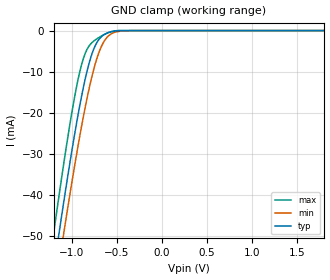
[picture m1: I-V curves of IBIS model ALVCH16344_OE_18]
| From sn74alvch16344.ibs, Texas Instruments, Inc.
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[Model]   ALVCH16344_OE_18
Model_type  Input
Vinl = 0.5775
Vinh = 1.2675
| variable   typ   min   max
C_comp   1.70pF   1.60pF   1.82pF
[Temperature Range]   40   100   -40
| Ambient temperature   25   85   -40
[Voltage range]   1.8   1.65   1.95
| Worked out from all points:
|   GND clamp passes 1 mA (typ) near -0.64 V on its own axis
[GND Clamp]
| ALVCH16344_OE_18
|   Voltage   I(typ)   I(min)   I(max)
-1.8V     -154.1mA   -159mA     -149mA
-1.2V     -58.39mA   -65.68mA   -49.51mA
-1.14V    -49.45mA   -56.93mA   -40.29mA
-1.09V    -42.19mA   -49.79mA   -32.85mA
-1.075V   -40.05mA   -47.68mA   -30.68mA
-970mV    -25.77mA   -33.43mA   -16.64mA
-885mV    -15.57mA   -22.84mA   -7.999mA
-785mV    -6.445mA   -12.18mA   -3.188mA
-695mV    -2.131mA   -5.276mA   -1.676mA
-590mV    -475.3uA   -1.289mA   -495.7uA
-450mV    -11.4uA    -130.5uA   -721.9nA
1.8V      1.117nA    59.63nA    5.149pA
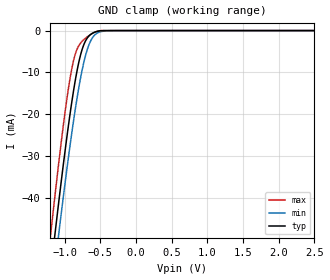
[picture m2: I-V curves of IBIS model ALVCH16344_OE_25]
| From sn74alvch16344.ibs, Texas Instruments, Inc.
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[Model]   ALVCH16344_OE_25
Model_type  Input
Vinl = 0.7
Vinh = 1.7
| variable   typ   min   max
C_comp   1.72pF   1.53pF   1.91pF
[Temperature Range]   40   100   -40
| Ambient temperature   25   85   -40
[Voltage range]   2.5   2.3   2.7
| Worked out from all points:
|   GND clamp passes 1 mA (typ) near -0.64 V on its own axis
[GND Clamp]
| ALVCH16344_OE_25
|   Voltage   I(typ)   I(min)   I(max)
-2.5V     -271.2mA   -273.1mA   -270.4mA
-1.2V     -58.39mA   -65.68mA   -49.51mA
-1.18V    -55.38mA   -62.74mA   -46.4mA
-1.13V    -47.98mA   -55.49mA   -38.78mA
-1.08V    -40.76mA   -48.38mA   -31.4mA
-960mV    -24.49mA   -32.13mA   -15.45mA
-865mV    -13.44mA   -20.52mA   -6.558mA
-740mV    -3.816mA   -8.342mA   -2.321mA
-675mV    -1.628mA   -4.185mA   -1.414mA
-605mV    -602.9uA   -1.621mA   -627.2uA
-365mV    -1.926uA   -30.65uA   -28.14nA
2.5V      1.121nA    59.64nA    7.252pA
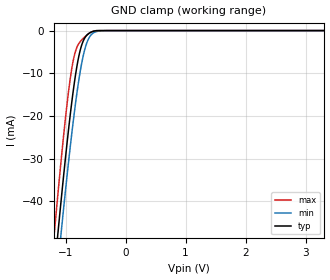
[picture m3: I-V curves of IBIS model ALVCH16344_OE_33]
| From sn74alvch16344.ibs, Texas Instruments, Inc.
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[Model]   ALVCH16344_OE_33
Model_type  Input
Vinl = 0.8
Vinh = 2.0
| variable   typ   min   max
C_comp   1.71pF   1.47pF   2.00pF
[Temperature Range]   40   100   -40
| Ambient temperature   25   85   -40
[Voltage range]   3.3   3   3.6
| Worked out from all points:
|   GND clamp passes 1 mA (typ) near -0.64 V on its own axis
[GND Clamp]
| ALVCH16344_OE_33
|   Voltage   I(typ)   I(min)   I(max)
-3.3V     -407.3mA   -405.9mA   -411.3mA
-1.19V    -56.88mA   -64.21mA   -47.95mA
-1.125V   -47.25mA   -54.77mA   -38.03mA
-1.085V   -41.47mA   -49.08mA   -32.13mA
-1.065V   -38.63mA   -46.28mA   -29.25mA
-960mV    -24.49mA   -32.13mA   -15.45mA
-860mV    -12.93mA   -19.95mA   -6.239mA
-740mV    -3.816mA   -8.342mA   -2.321mA
-665mV    -1.42mA    -3.702mA   -1.288mA
-585mV    -437.3uA   -1.192mA   -455.1uA
-350mV    -1.412uA   -23.67uA   -16.13nA
3.3V      1.125nA    59.65nA    9.668pA
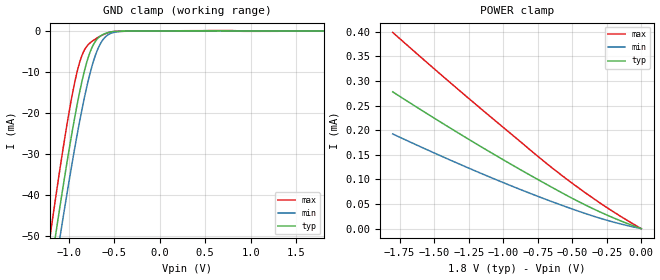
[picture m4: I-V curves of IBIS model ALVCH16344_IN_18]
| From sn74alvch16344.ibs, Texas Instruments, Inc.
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[Model]   ALVCH16344_IN_18
Model_type  Input
Vinl = 0.5775
Vinh = 1.2675
| variable   typ   min   max
C_comp   2.46pF   2.18pF   2.79pF
[Temperature Range]   40   100   -40
| Ambient temperature   25   85   -40
[Voltage range]   1.8   1.65   1.95
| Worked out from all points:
|   GND clamp passes 1 mA (typ) near -0.63 V on its own axis
[GND Clamp]
| ALVCH16344_IN_18
|   Voltage   I(typ)   I(min)   I(max)
-1.8V     -154.5mA   -159.2mA   -149.5mA
-1.205V   -59.36mA   -66.56mA   -50.62mA
-1.185V   -56.34mA   -63.61mA   -47.5mA
-1.145V   -50.39mA   -57.78mA   -41.35mA
-1.09V    -42.38mA   -49.91mA   -33.15mA
-970mV    -25.94mA   -33.53mA   -16.89mA
-885mV    -15.72mA   -22.93mA   -8.227mA
-785mV    -6.577mA   -12.27mA   -3.385mA
-695mV    -2.245mA   -5.349mA   -1.845mA
-605mV    -699.2uA   -1.682mA   -770uA
-465mV    -85uA      -212uA     -105.7uA
1.8V      1.12nA     9.574uA    -22.72uA
[POWER Clamp]
| ALVCH16344_IN_18
|   Voltage   I(typ)   I(min)   I(max)
-1.8V     278uA      192.5uA    398.9uA
-1.2V     173.2uA    117.1uA    252.9uA
-645mV    83.65uA    54.66uA    123.4uA
-480mV    58.73uA    37.93uA    88.08uA
-315mV    36.04uA    22.58uA    55.28uA
-155mV    16.49uA    9.93uA     25.95uA
-16.28fV  1.12nA     59.64nA    8.716pA
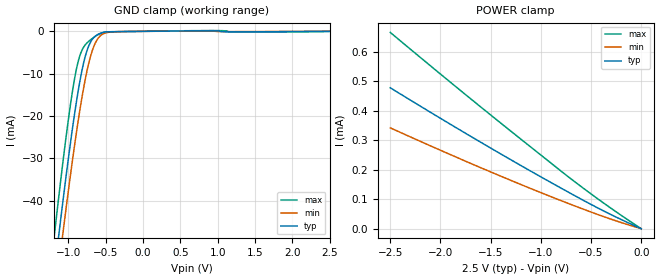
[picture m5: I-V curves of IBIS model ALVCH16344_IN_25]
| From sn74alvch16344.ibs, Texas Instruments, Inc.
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[Model]   ALVCH16344_IN_25
Model_type  Input
Vinl = 0.7
Vinh = 1.7
| variable   typ   min   max
C_comp   2.54pF   2.03pF   2.93pF
[Temperature Range]   40   100   -40
| Ambient temperature   25   85   -40
[Voltage range]   2.5   2.3   2.7
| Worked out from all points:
|   GND clamp passes 1 mA (typ) near -0.63 V on its own axis
[GND Clamp]
| ALVCH16344_IN_25
|   Voltage   I(typ)   I(min)   I(max)
-2.5V     -271.7mA   -273.5mA   -271.2mA
-1.195V   -57.91mA   -65.13mA   -49.13mA
-1.16V    -52.67mA   -60mA      -43.71mA
-1.125V   -47.5mA    -54.94mA   -38.4mA
-1.075V   -40.29mA   -47.84mA   -31.04mA
-960mV    -24.7mA    -32.27mA   -15.77mA
-865mV    -13.63mA   -20.65mA   -6.836mA
-745mV    -4.221mA   -8.841mA   -2.636mA
-670mV    -1.665mA   -4.035mA   -1.559mA
-600mV    -685.2uA   -1.589mA   -766.6uA
-305mV    -60.79uA   -50.66uA   -89.26uA
2.5V      1.125nA    20.81uA    -42.68uA
[POWER Clamp]
| ALVCH16344_IN_25
|   Voltage   I(typ)   I(min)   I(max)
-2.5V     477.5uA    341.7uA    665.3uA
-1.6V     293.2uA    206.8uA    412.9uA
-775mV    133uA      91.91uA    188.8uA
-380mV    61.1uA     41.52uA    88.18uA
-31.15fV  1.125nA    59.64nA    12.15pA
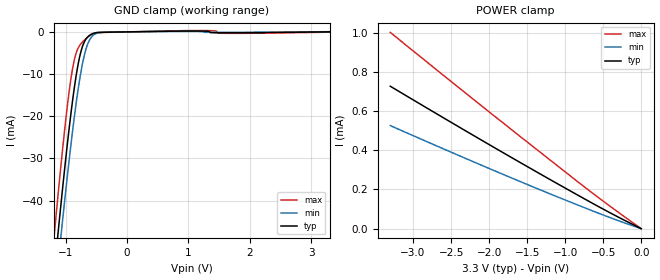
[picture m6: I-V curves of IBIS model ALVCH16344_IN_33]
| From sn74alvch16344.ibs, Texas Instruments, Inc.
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[Model]   ALVCH16344_IN_33
Model_type  Input
Vinl = 0.8
Vinh = 2.0
| variable   typ   min   max
C_comp   2.58pF   1.96pF   3.05pF
[Temperature Range]   40   100   -40
| Ambient temperature   25   85   -40
[Voltage range]   3.3   3   3.6
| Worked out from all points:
|   GND clamp passes 1 mA (typ) near -0.63 V on its own axis
[GND Clamp]
| ALVCH16344_IN_33
|   Voltage   I(typ)   I(min)   I(max)
-3.3V     -408.2mA   -406.6mA   -412.6mA
-1.185V   -56.46mA   -63.7mA    -47.64mA
-1.12V    -46.83mA   -54.26mA   -37.72mA
-1.08V    -41.05mA   -48.58mA   -31.82mA
-1.065V   -38.92mA   -46.47mA   -29.67mA
-950mV    -23.49mA   -31.02mA   -14.67mA
-860mV    -13.16mA   -20.11mA   -6.569mA
-730mV    -3.559mA   -7.722mA   -2.445mA
-655mV    -1.41mA    -3.379mA   -1.412mA
-580mV    -552.6uA   -1.206mA   -633.9uA
-270mV    -67.94uA   -51.6uA    -98.78uA
3.3V      1.131nA    40.72uA    -79.23uA
[POWER Clamp]
| ALVCH16344_IN_33
|   Voltage   I(typ)   I(min)   I(max)
-3.3V     726.6uA    525.8uA    1.001mA
-1.955V   418.9uA    299.7uA    582uA
-845mV    173.4uA    122.2uA    242.6uA
-430mV    85.18uA    59.42uA    120.2uA
-48.03fV  1.131nA    59.65nA    16.28pA
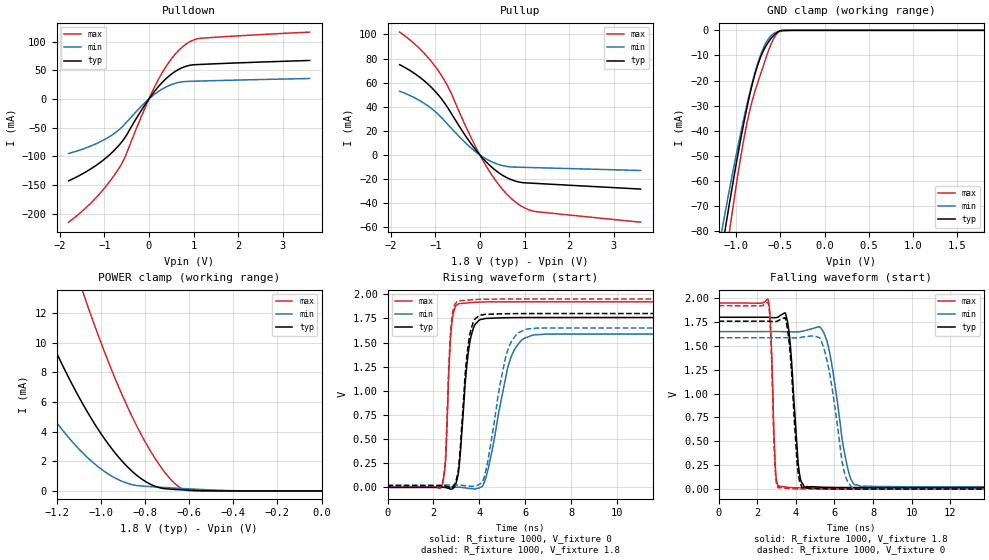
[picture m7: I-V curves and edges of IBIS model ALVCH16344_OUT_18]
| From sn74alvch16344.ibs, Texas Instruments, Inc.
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[Model]   ALVCH16344_OUT_18
Model_type  3-state
Enable   Active-Low
Vref =   0
Rref =   1000
Cref =   30p
Vmeas =   0.9
| variable   typ   min   max
C_comp   4.31pF   3.88pF   4.55pF
| C_pullup   5.53pF   4.17pF   6.17pF
| C_pulldown   8.54pF   4.73pF   11.91pF
| C_tri-state   4.31pF   3.88pF   4.55pF
[Temperature Range]   40   100   -40
| Ambient temperature   25   85   -40
[Voltage range]   1.8   1.65   1.95
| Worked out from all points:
|   slope of the pulldown table from 0 to 0.27 V, typ, clamps not added: 10.2 ohm
|   slope of the pullup table from 0 to 0.27 V, typ, clamps not added: 26.4 ohm
|   GND clamp passes 1 mA (typ) near -0.54 V on its own axis
|   POWER clamp passes 1 mA (typ) near -0.83 V on its own axis
|   rising waveform, R_fixture 1000, V_fixture 0: 20-80 % time 355ps typ, 776ps min, 195ps max; typ from 0 V to 1.76 V
|   falling waveform, R_fixture 1000, V_fixture 1.8: 20-80 % time 344ps typ, 701ps min, 181ps max; typ from 1.8 V to 0.016 V
|   rising waveform, R_fixture 1000, V_fixture 1.8: 20-80 % time 339ps typ, 702ps min, 189ps max; typ from 0.016 V to 1.8 V
|   falling waveform, R_fixture 1000, V_fixture 0: 20-80 % time 329ps typ, 676ps min, 176ps max; typ from 1.76 V to 0 V
[GND Clamp]
| ALVCH16344_OUT_18
|   Voltage   I(typ)   I(min)   I(max)
-1.8V     -239.8mA   -213.3mA   -281.9mA
-1.165V   -87.9mA    -80.05mA   -102.5mA
-1.145V   -83.5mA    -76.2mA    -97.32mA
-1.125V   -79.14mA   -72.37mA   -92.17mA
-1.105V   -74.82mA   -68.59mA   -87.08mA
-1.07V    -67.39mA   -62.07mA   -78.32mA
-915mV    -36.93mA   -35.13mA   -43.44mA
-800mV    -18.87mA   -18.34mA   -25.63mA
-685mV    -7.555mA   -6.459mA   -13.16mA
-570mV    -1.813mA   -1.117mA   -2.886mA
-480mV    -40.69uA   -266.3uA   -17.64uA
1.8V      1.174nA    70.33nA    30.13pA
[POWER Clamp]
| ALVCH16344_OUT_18
|   Voltage   I(typ)   I(min)   I(max)
-1.8V     34.01mA    21.32mA    54.93mA
-1.545V   22.31mA    13.18mA    38.34mA
-1.31V    13.03mA    6.974mA    24.71mA
-1.19V    9.01mA     4.426mA    18.52mA
-1.08V    5.839mA    2.547mA    13.4mA
-1.065V   5.45mA     2.328mA    12.75mA
-925mV    2.384mA    795.1uA    7.238mA
-850mV    1.219mA    400.6uA    4.773mA
-770mV    413.1uA    285.9uA    2.574mA
-695mV    133.3uA    217.1uA    977.5uA
-635mV    77.68uA    166.6uA    176.9uA
-16.28fV  1.174nA    59.89nA    35.89pA
[Pulldown]
| ALVCH16344_OUT_18
|   Voltage   I(typ)   I(min)   I(max)
-1.8V     -142.5mA   -94.94mA   -214.6mA
-1.19V    -116mA     -78.22mA   -172.4mA
-925mV    -100.1mA   -67.55mA   -148.4mA
-685mV    -81.85mA   -54.5mA    -122.3mA
-535mV    -66.98mA   -43.37mA   -101mA
-105mV    -12.13mA   -7.634mA   -18.73mA
200mV     20.41mA    12.38mA    32.16mA
490mV     42.45mA    24.65mA    68.46mA
785mV     55.72mA    30.25mA    92.88mA
970mV     59.35mA    30.84mA    101.8mA
1.155V    60.2mA     31.26mA    105.7mA
3.6V      67.09mA    35.62mA    116.5mA
[Pullup]
| ALVCH16344_OUT_18
|   Voltage   I(typ)   I(min)   I(max)
-1.8V     74.92mA    52.9mA     101.9mA
-1.32V    63.68mA    44.5mA     87.1mA
-1.11V    56.9mA     39.25mA    78.51mA
-920mV    49.28mA    33.21mA    69.13mA
-685mV    37.02mA    23.92mA    54.42mA
-245mV    11.73mA    7.31mA     17.97mA
115mV     -4.735mA   -2.729mA   -7.61mA
450mV     -15.41mA   -8.179mA   -25.94mA
790mV     -21.56mA   -9.992mA   -38.78mA
1.02V     -23.05mA   -10.23mA   -44.17mA
1.255V    -23.52mA   -10.47mA   -46.95mA
3.6V      -28.2mA    -12.79mA   -55.66mA
[Ramp]
| ALVCH16344_OUT_18
| variable   typ   min   max
dV/dt_r   1.07/3.71E-10   0.96/8.06E-10   1.16/2.04E-10
dV/dt_f   1.10/3.69E-10   1.01/7.84E-10   1.19/1.93E-10
R_load = 1000
[Rising Waveform]
| ALVCH16344_OUT_18
R_fixture =   1000
C_fixture =   0
L_fixture =   0
V_fixture =   0
V_fixture_min = 0
V_fixture_max = 0
|   Time   V(typ)   V(min)   V(max)
0s        317pV      1.868nV    220.5pV
2.39ns    1.125mV    374.2uV    29.72mV
2.53ns    -1.146mV   791uV      298mV
2.775ns   -18.62mV   2.02mV     1.639V
3.105ns   189.5mV    1.383mV    1.902V
3.545ns   1.445V     -10.76mV   1.912V
4.055ns   1.74V      925.5uV    1.919V
5.34ns    1.758V     1.321V     1.922V
6.265ns   1.759V     1.573V     1.922V
24.99ns   1.759V     1.586V     1.922V
[Falling Waveform]
| ALVCH16344_OUT_18
R_fixture =   1000
C_fixture =   0
L_fixture =   0
V_fixture =   1.8
V_fixture_min = 1.65
V_fixture_max = 1.95
|   Time   V(typ)   V(min)   V(max)
0s        1.8V       1.65V      1.95V
2.575ns   1.799V     1.65V      1.979V
2.94ns    1.796V     1.65V      223.6mV
3.095ns   1.804V     1.65V      28.1mV
3.605ns   1.705V     1.648V     17.63mV
4.12ns    271.8mV    1.647V     12.35mV
4.47ns    19.14mV    1.66V      11.31mV
5.61ns    17.54mV    1.552V     10.87mV
7.07ns    15.83mV    43.63mV    11.06mV
24.99ns   15.91mV    23.52mV    11.08mV
[Rising Waveform]
| ALVCH16344_OUT_18
R_fixture =   1000
C_fixture =   0
L_fixture =   0
V_fixture =   1.8
V_fixture_min = 1.65
V_fixture_max = 1.95
|   Time   V(typ)   V(min)   V(max)
0s        15.91mV    23.52mV    11.08mV
2.39ns    16.5mV     23.74mV    43.7mV
2.53ns    14.07mV    24.03mV    330.4mV
2.76ns    -1.128mV   24.83mV    1.651V
3.06ns    149.3mV    23.74mV    1.929V
3.515ns   1.48V      13.57mV    1.94V
4.035ns   1.785V     37.42mV    1.947V
5.185ns   1.798V     1.381V     1.95V
6.01ns    1.8V       1.635V     1.95V
24.99ns   1.8V       1.65V      1.95V
[Falling Waveform]
| ALVCH16344_OUT_18
R_fixture =   1000
C_fixture =   0
L_fixture =   0
V_fixture =   0
V_fixture_min = 0
V_fixture_max = 0
|   Time   V(typ)   V(min)   V(max)
0s        1.759V     1.586V     1.922V
2.575ns   1.758V     1.586V     1.945V
2.93ns    1.756V     1.586V     206.5mV
3.085ns   1.763V     1.586V     12.37mV
3.57ns    1.671V     1.585V     6.125mV
4.07ns    260.1mV    1.585V     1.226mV
4.355ns   11.68mV    1.592V     262.3uV
5.415ns   1.588mV    1.497V     -226.1uV
7.005ns   -145.7uV   1.31mV     -20.82uV
24.99ns   16.37nV    28.73nV    1.495nV
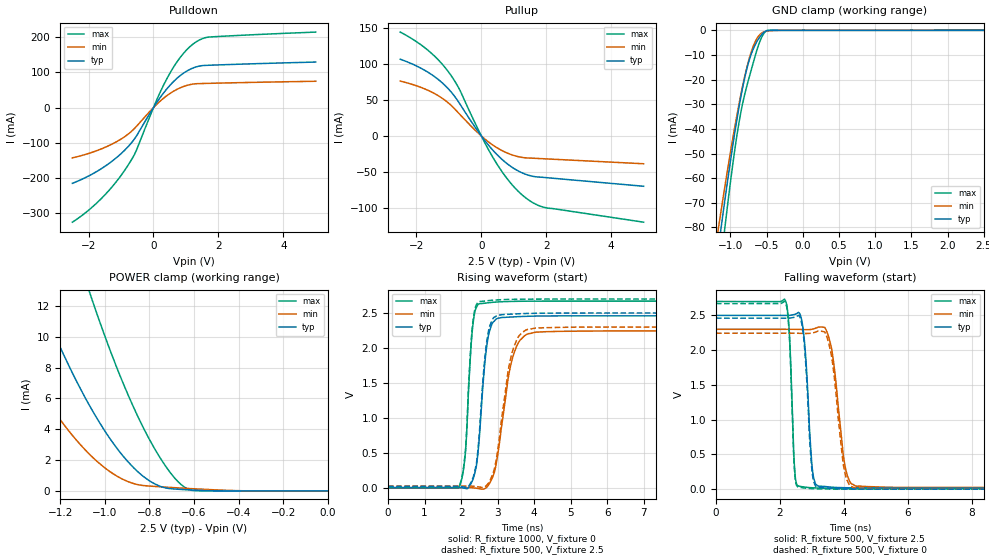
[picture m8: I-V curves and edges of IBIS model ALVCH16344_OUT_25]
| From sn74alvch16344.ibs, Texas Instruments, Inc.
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[Model]   ALVCH16344_OUT_25
Model_type  3-state
Enable   Active-Low
Vref =   0
Rref =   500
Cref =   30p
Vmeas =   1.25
| variable   typ   min   max
C_comp   4.16pF   3.75pF   4.35pF
| C_pullup   5.54pF   4.59pF   6.36pF
| C_pulldown   8.13pF   4.63pF   11.53pF
| C_tri-state   4.16pF   3.75pF   4.35pF
[Temperature Range]   40   100   -40
| Ambient temperature   25   85   -40
[Voltage range]   2.5   2.3   2.7
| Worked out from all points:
|   slope of the pulldown table from 0 to 0.375 V, typ, clamps not added: 7.66 ohm
|   slope of the pullup table from 0 to 0.375 V, typ, clamps not added: 17.9 ohm
|   GND clamp passes 1 mA (typ) near -0.54 V on its own axis
|   POWER clamp passes 1 mA (typ) near -0.83 V on its own axis
|   rising waveform, R_fixture 1000, V_fixture 0: 20-80 % time 228ps typ, 381ps min, 164ps max; typ from 0 V to 2.46 V
|   falling waveform, R_fixture 500, V_fixture 2.5: 20-80 % time 185ps typ, 311ps min, 125ps max; typ from 2.5 V to 0.017 V
|   rising waveform, R_fixture 500, V_fixture 2.5: 20-80 % time 225ps typ, 368ps min, 163ps max; typ from 0.017 V to 2.5 V
|   falling waveform, R_fixture 500, V_fixture 0: 20-80 % time 180ps typ, 305ps min, 124ps max; typ from 2.46 V to 0 V
[GND Clamp]
| ALVCH16344_OUT_25
|   Voltage   I(typ)   I(min)   I(max)
-2.5V     -419.5mA   -371.2mA   -493.5mA
-1.165V   -87.9mA    -80.05mA   -102.5mA
-1.12V    -78.06mA   -71.43mA   -90.89mA
-1.08V    -69.5mA    -63.92mA   -80.8mA
-1.06V    -65.29mA   -60.23mA   -75.86mA
-910mV    -36.04mA   -34.32mA   -42.49mA
-800mV    -18.87mA   -18.34mA   -25.63mA
-740mV    -12.06mA   -11.37mA   -18.94mA
-675mV    -6.887mA   -5.734mA   -12.11mA
-560mV    -1.484mA   -929.3uA   -2.306mA
-485mV    -51.11uA   -287.8uA   -29.09uA
2.5V      1.2nA      109.6nA    42.05pA
[POWER Clamp]
| ALVCH16344_OUT_25
|   Voltage   I(typ)   I(min)   I(max)
-2.5V     71.94mA    48.59mA    107mA
-1.535V   21.88mA    12.89mA    37.73mA
-1.515V   21.03mA    12.31mA    36.5mA
-1.295V   12.5mA     6.63mA     23.91mA
-1.165V   8.243mA    3.958mA    17.31mA
-1.06V    5.323mA    2.257mA    12.53mA
-950mV    2.851mA    997uA      8.139mA
-845mV    1.155mA    386.3uA    4.622mA
-745mV    265.4uA    262uA      1.988mA
-655mV    94.31uA    183.1uA    377.2uA
-600mV    52.05uA    138.6uA    18.79uA
-31.15fV  1.2nA      59.93nA    49.78pA
[Pulldown]
| ALVCH16344_OUT_25
|   Voltage   I(typ)   I(min)   I(max)
-2.5V     -214.5mA   -142.4mA   -324.7mA
-1.625V   -174.1mA   -117.7mA   -259.4mA
-1.225V   -148.2mA   -100.9mA   -219mA
-870mV    -119.1mA   -81.21mA   -175.4mA
-550mV    -84.06mA   -55.74mA   -125.8mA
75mV      10.83mA    7.022mA    16.48mA
430mV     55.09mA    35.04mA    84.84mA
820mV     90.47mA    55.98mA    141.7mA
1.215V    112.2mA    66.71mA    179.9mA
1.465V    118.6mA    68.28mA    193.9mA
1.72V     120.2mA    68.88mA    200.2mA
5V        129.2mA    74.77mA    214.1mA
[Pullup]
| ALVCH16344_OUT_25
|   Voltage   I(typ)   I(min)   I(max)
-2.5V     107.1mA    76.58mA    144.9mA
-1.67V    89.59mA    64.21mA    120.5mA
-1.33V    78.85mA    56.22mA    106.3mA
-1.03V    66.34mA    46.59mA    90.37mA
-685mV    46.19mA    31.15mA    65.85mA
20mV      -1.239mA   -810.3uA   -1.829mA
425mV     -23.31mA   -14.81mA   -35.12mA
890mV     -41.88mA   -25.49mA   -64.98mA
1.355V    -53.24mA   -30.42mA   -85.9mA
1.67V     -56.84mA   -31.17mA   -95.02mA
1.985V    -58.03mA   -31.89mA   -100.1mA
5V        -70.11mA   -38.72mA   -120.2mA
[Ramp]
| ALVCH16344_OUT_25
| variable   typ   min   max
dV/dt_r   1.49/2.38E-10   1.36/4.20E-10   1.61/1.69E-10
dV/dt_f   1.52/1.96E-10   1.38/3.31E-10   1.63/1.30E-10
R_load = 1000
[Rising Waveform]
| ALVCH16344_OUT_25
R_fixture =   1000
C_fixture =   0
L_fixture =   0
V_fixture =   0
V_fixture_min = 0
V_fixture_max = 0
|   Time   V(typ)   V(min)   V(max)
0s        336.5pV    1.499nV    239.1pV
1.945ns   144.4uV    283.6uV    7.174mV
2.12ns    -10.65mV   302.7uV    512.2mV
2.315ns   107.4mV    -2.261mV   2.297V
2.49ns    664.4mV    -13.79mV   2.632V
2.67ns    1.891V     -7.327mV   2.643V
2.84ns    2.338V     125.4mV    2.653V
3.415ns   2.445V     1.871V     2.667V
3.995ns   2.456V     2.222V     2.67V
24.99ns   2.46V      2.244V     2.671V
[Falling Waveform]
| ALVCH16344_OUT_25
R_fixture =   500
C_fixture =   0
L_fixture =   0
V_fixture =   2.5
V_fixture_min = 2.3
V_fixture_max = 2.7
|   Time   V(typ)   V(min)   V(max)
0s        2.5V       2.3V       2.7V
2.165ns   2.499V     2.3V       2.717V
2.29ns    2.5V       2.3V       2.277V
2.465ns   2.515V     2.3V       244.5mV
2.605ns   2.534V     2.298V     40.46mV
3.01ns    298.8mV    2.301V     20.07mV
3.2ns     43.52mV    2.331V     16.62mV
3.58ns    30.12mV    2.091V     13.44mV
4.39ns    18.26mV    42.45mV    11.92mV
24.99ns   16.87mV    23.84mV    12mV
[Rising Waveform]
| ALVCH16344_OUT_25
R_fixture =   500
C_fixture =   0
L_fixture =   0
V_fixture =   2.5
V_fixture_min = 2.3
V_fixture_max = 2.7
|   Time   V(typ)   V(min)   V(max)
0s        16.87mV    23.84mV    12mV
1.945ns   16.72mV    23.72mV    19.83mV
2.12ns    6.448mV    23.54mV    542.5mV
2.315ns   129.7mV    21.01mV    2.339V
2.485ns   690.5mV    10.81mV    2.664V
2.65ns    1.862V     13.13mV    2.672V
2.795ns   2.331V     110.6mV    2.68V
3.375ns   2.485V     1.893V     2.696V
3.84ns    2.494V     2.269V     2.699V
24.99ns   2.5V       2.3V       2.7V
[Falling Waveform]
| ALVCH16344_OUT_25
R_fixture =   500
C_fixture =   0
L_fixture =   0
V_fixture =   0
V_fixture_min = 0
V_fixture_max = 0
|   Time   V(typ)   V(min)   V(max)
0s        2.46V      2.244V     2.671V
2.165ns   2.459V     2.244V     2.686V
2.285ns   2.46V      2.244V     2.275V
2.46ns    2.473V     2.244V     237.9mV
2.6ns     2.493V     2.242V     26.09mV
2.765ns   2.058V     2.24V      16.32mV
3ns       269.4mV    2.245V     7.49mV
3.19ns    23.04mV    2.274V     4.269mV
4.345ns   1.13mV     15.38mV    -72.06uV
24.99ns   10.8nV     -10.26nV   -473.8pV
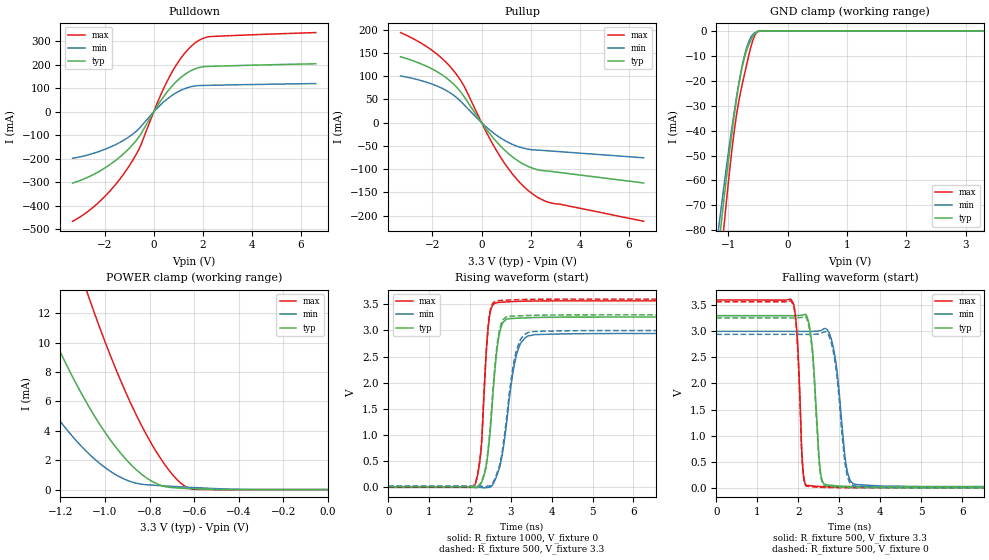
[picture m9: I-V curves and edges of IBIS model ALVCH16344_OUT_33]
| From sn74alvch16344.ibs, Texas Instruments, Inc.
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[Model]   ALVCH16344_OUT_33
Model_type  3-state
Enable   Active-Low
Vref =   0
Rref =   500
Cref =   50p
Vmeas =   1.5
| variable   typ   min   max
C_comp   4.02pF   3.63pF   4.20pF
| C_pullup   5.42pF   4.43pF   6.33pF
| C_pulldown   7.92pF   4.36pF   12.15pF
| C_tri-state   4.02pF   3.63pF   4.20pF
[Temperature Range]   40   100   -40
| Ambient temperature   25   85   -40
[Voltage range]   3.3   3   3.6
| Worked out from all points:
|   slope of the pulldown table from 0 to 0.495 V, typ, clamps not added: 6.36 ohm
|   slope of the pullup table from 0 to 0.495 V, typ, clamps not added: 14.4 ohm
|   GND clamp passes 1 mA (typ) near -0.54 V on its own axis
|   POWER clamp passes 1 mA (typ) near -0.83 V on its own axis
|   rising waveform, R_fixture 1000, V_fixture 0: 20-80 % time 217ps typ, 307ps min, 153ps max; typ from 0 V to 3.26 V
|   falling waveform, R_fixture 500, V_fixture 3.3: 20-80 % time 152ps typ, 217ps min, 111ps max; typ from 3.3 V to 0.019 V
|   rising waveform, R_fixture 500, V_fixture 3.3: 20-80 % time 216ps typ, 303ps min, 152ps max; typ from 0.019 V to 3.3 V
|   falling waveform, R_fixture 500, V_fixture 0: 20-80 % time 151ps typ, 214ps min, 110ps max; typ from 3.26 V to 0 V
[GND Clamp]
| ALVCH16344_OUT_33
|   Voltage   I(typ)   I(min)   I(max)
-3.3V     -630.9mA   -557.1mA   -742.1mA
-1.17V    -89.01mA   -81.02mA   -103.8mA
-1.14V    -82.41mA   -75.24mA   -96.03mA
-1.115V   -76.98mA   -70.48mA   -89.62mA
-1.07V    -67.39mA   -62.07mA   -78.32mA
-895mV    -33.42mA   -31.95mA   -39.71mA
-775mV    -15.78mA   -15.25mA   -22.74mA
-705mV    -9.02mA    -8.068mA   -15.26mA
-640mV    -4.84mA    -3.606mA   -8.531mA
-570mV    -1.813mA   -1.117mA   -2.886mA
-500mV    -158.1uA   -362.5uA   -174.5uA
3.3V      1.233nA    1.136uA    55.05pA
[POWER Clamp]
| ALVCH16344_OUT_33
|   Voltage   I(typ)   I(min)   I(max)
-3.3V     121.5mA    84.88mA    173.7mA
-1.545V   22.31mA    13.18mA    38.34mA
-1.32V    13.39mA    7.207mA    25.25mA
-1.295V   12.5mA     6.63mA     23.91mA
-1.195V   9.166mA    4.523mA    18.77mA
-1.075V   5.709mA    2.473mA    13.18mA
-965mV    3.149mA    1.134mA    8.698mA
-860mV    1.353mA    433.9uA    5.08mA
-760mV    347.7uA    276.2uA    2.334mA
-660mV    98.72uA    187.3uA    438.8uA
-605mV    55.45uA    142.5uA    25.78uA
-48.03fV  1.233nA    59.98nA    66.75pA
[Pulldown]
| ALVCH16344_OUT_33
|   Voltage   I(typ)   I(min)   I(max)
-3.3V     -302.4mA   -196.9mA   -465.1mA
-2.73V    -280.1mA   -184.3mA   -427.4mA
-2.165V   -249.6mA   -165.9mA   -377.5mA
-1.615V   -211.3mA   -142.1mA   -316.4mA
-1.11V    -166.7mA   -113.2mA   -247.3mA
-565mV    -100.8mA   -67.09mA   -151.3mA
185mV     31.43mA    20.51mA    47.78mA
665mV     100mA      64.12mA    153.8mA
1.17V     151.9mA    95.01mA    237.4mA
1.67V     182.8mA    110.5mA    291.9mA
2.31V     194mA      113.5mA    320.7mA
6.6V      205mA      120.8mA    337.8mA
[Pullup]
| ALVCH16344_OUT_33
|   Voltage   I(typ)   I(min)   I(max)
-3.3V     141.8mA    100.5mA    193.8mA
-2.055V   116.6mA    83.64mA    157mA
-1.565V   101.2mA    72.65mA    135.9mA
-1.15V    83.38mA    59.35mA    112.5mA
-690mV    54.23mA    37.12mA    76.31mA
185mV     -13.61mA   -9.123mA   -19.68mA
760mV     -49.81mA   -32.56mA   -73.33mA
1.385V    -78.74mA   -49.67mA   -118.8mA
2.005V    -96.74mA   -58.07mA   -150.8mA
2.41V     -102.8mA   -59.57mA   -164.6mA
2.815V    -105mA     -61.13mA   -172.8mA
6.6V      -129.9mA   -75.75mA   -212.4mA
[Ramp]
| ALVCH16344_OUT_33
| variable   typ   min   max
dV/dt_r   1.96/2.29E-10   1.77/3.22E-10   2.14/1.55E-10
dV/dt_f   1.98/1.54E-10   1.82/2.27E-10   2.16/1.16E-10
R_load = 1000
[Rising Waveform]
| ALVCH16344_OUT_33
R_fixture =   1000
C_fixture =   0
L_fixture =   0
V_fixture =   0
V_fixture_min = 0
V_fixture_max = 0
|   Time   V(typ)   V(min)   V(max)
0s        370.2pV    1.359nV    266.5pV
2.12ns    -6.329mV   1.423mV    44.71mV
2.27ns    75.04mV    -3.654mV   708.9mV
2.39ns    378.5mV    -7.946mV   2.479V
2.465ns   843.7mV    -1.527mV   3.2V
2.67ns    2.7V       254.7mV    3.534V
2.81ns    3.157V     728.6mV    3.544V
3.135ns   3.233V     2.521V     3.557V
3.56ns    3.248V     2.918V     3.564V
24.99ns   3.257V     2.942V     3.567V
[Falling Waveform]
| ALVCH16344_OUT_33
R_fixture =   500
C_fixture =   0
L_fixture =   0
V_fixture =   3.3
V_fixture_min = 3
V_fixture_max = 3.6
|   Time   V(typ)   V(min)   V(max)
0s        3.3V       3V         3.6V
1.86ns    3.299V     3V         3.564V
1.975ns   3.302V     3V         2.851V
2.11ns    3.313V     2.999V     380.4mV
2.205ns   3.291V     2.998V     46.05mV
2.345ns   2.644V     3V         36.67mV
2.53ns    371.3mV    3.012V     25.39mV
2.685ns   56.46mV    3.043V     21.02mV
3.37ns    23.99mV    70.84mV    14.39mV
24.99ns   18.55mV    25.67mV    13.37mV
[Rising Waveform]
| ALVCH16344_OUT_33
R_fixture =   500
C_fixture =   0
L_fixture =   0
V_fixture =   3.3
V_fixture_min = 3
V_fixture_max = 3.6
|   Time   V(typ)   V(min)   V(max)
0s        18.55mV    25.67mV    13.37mV
2.12ns    12.12mV    26.65mV    58.75mV
2.27ns    95.43mV    21.51mV    737.4mV
2.39ns    407mV      17.8mV     2.527V
2.465ns   897.1mV    25.2mV     3.243V
2.665ns   2.735V     280.1mV    3.567V
2.805ns   3.203V     775.5mV    3.577V
3.105ns   3.277V     2.515V     3.588V
3.44ns    3.288V     2.965V     3.595V
24.99ns   3.3V       3V         3.6V
[Falling Waveform]
| ALVCH16344_OUT_33
R_fixture =   500
C_fixture =   0
L_fixture =   0
V_fixture =   0
V_fixture_min = 0
V_fixture_max = 0
|   Time   V(typ)   V(min)   V(max)
0s        3.257V     2.942V     3.567V
1.86ns    3.256V     2.942V     3.53V
1.97ns    3.259V     2.942V     2.865V
2.105ns   3.269V     2.942V     391.7mV
2.205ns   3.246V     2.941V     29.18mV
2.34ns    2.622V     2.942V     22.01mV
2.53ns    313.7mV    2.954V     11.13mV
2.68ns    34.15mV    2.986V     7.187mV
3.35ns    5.097mV    39.59mV    1.008mV
24.99ns   -2.948nV   3.68nV     -1.333nV
